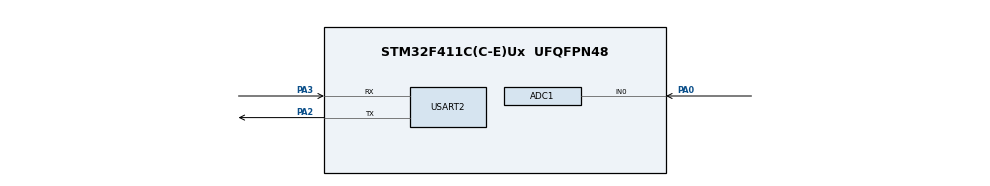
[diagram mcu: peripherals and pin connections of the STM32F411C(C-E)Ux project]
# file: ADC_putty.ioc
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ADC1.Channel-0\#ChannelRegularConversion=ADC_CHANNEL_0
ADC1.DMAContinuousRequests=ENABLE
ADC1.NbrOfConversionFlag=1
ADC1.Rank-0\#ChannelRegularConversion=1
ADC1.SamplingTime-0\#ChannelRegularConversion=ADC_SAMPLETIME_3CYCLES
ADC1.master=1
Dma.ADC1.0.Direction=DMA_PERIPH_TO_MEMORY
Dma.ADC1.0.FIFOMode=DMA_FIFOMODE_DISABLE
Dma.ADC1.0.Instance=DMA2_Stream0
Dma.ADC1.0.MemDataAlignment=DMA_MDATAALIGN_HALFWORD
Dma.ADC1.0.MemInc=DMA_MINC_ENABLE
Dma.ADC1.0.Mode=DMA_NORMAL
Dma.ADC1.0.PeriphDataAlignment=DMA_PDATAALIGN_HALFWORD
Dma.ADC1.0.PeriphInc=DMA_PINC_DISABLE
Dma.ADC1.0.Priority=DMA_PRIORITY_LOW
Dma.Request0=ADC1
Mcu.Family=STM32F4
Mcu.Name=STM32F411C(C-E)Ux
Mcu.Package=UFQFPN48
NVIC.ADC_IRQn=true\:0\:0\:false\:false\:true\:true\:true\:true
NVIC.DMA2_Stream0_IRQn=true\:0\:0\:false\:false\:true\:false\:true\:true
NVIC.PriorityGroup=NVIC_PRIORITYGROUP_4
NVIC.TIM2_IRQn=true\:0\:0\:false\:false\:true\:true\:true\:true
PA0-WKUP.Signal=ADCx_IN0
PA2.Mode=Asynchronous
PA2.Signal=USART2_TX
PA3.Mode=Asynchronous
PA3.Signal=USART2_RX
ProjectManager.HeapSize=0x200
ProjectManager.StackSize=0x400
ProjectManager.TargetToolchain=STM32CubeIDE
RCC.48MHZClocksFreq_Value=168000000
RCC.AHBFreq_Value=16000000
RCC.APB1CLKDivider=RCC_HCLK_DIV2
RCC.APB1Freq_Value=8000000
RCC.APB1TimFreq_Value=16000000
RCC.APB2Freq_Value=16000000
RCC.APB2TimFreq_Value=16000000
RCC.CortexFreq_Value=16000000
RCC.HCLKFreq_Value=16000000
RCC.HSE_VALUE=25000000
RCC.HSI_VALUE=16000000
RCC.LSE_VALUE=32768
RCC.PLLM=8
RCC.PLLN=336
RCC.PLLP=RCC_PLLP_DIV4
RCC.SYSCLKFreq_VALUE=16000000
RCC.VCOOutputFreq_Value=672000000
SH.ADCx_IN0.0=ADC1_IN0,IN0
TIM2.Prescaler=8399
TIM2.TIM_MasterOutputTrigger=TIM_TRGO_UPDATE
USART2.VirtualMode=VM_ASYNC
VP_TIM2_VS_ClockSourceINT.Mode=Internal
board=custom

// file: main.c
/* USER CODE BEGIN Header */
/**
  ******************************************************************************
  * @file           : main.c
  * @brief          : Main program body
  ******************************************************************************
  * @attention
  *
  * Copyright (c) 2026 STMicroelectronics.
  * All rights reserved.
  *
  * This software is licensed under terms that can be found in the LICENSE file
  * in the root directory of this software component.
  * If no LICENSE file comes with this software, it is provided AS-IS.
  *
  ******************************************************************************
  */
/* USER CODE END Header */
#include "main.h"
#include <stdio.h>
#include <string.h>

ADC_HandleTypeDef hadc1;
DMA_HandleTypeDef hdma_adc1;

TIM_HandleTypeDef htim2;

UART_HandleTypeDef huart2;

/* USER CODE BEGIN PV */
uint16_t adc_buffer[1];
/* USER CODE END PV */

void SystemClock_Config(void);
static void MX_GPIO_Init(void);
static void MX_DMA_Init(void);
static void MX_ADC1_Init(void);
static void MX_TIM2_Init(void);
static void MX_USART2_UART_Init(void);

/* USER CODE BEGIN 0 */
uint16_t adc_buffer[1];
/* USER CODE END 0 */

int main(void)
{

  /* MCU Configuration--------------------------------------------------------*/

  /* Reset of all peripherals, Initializes the Flash interface and the Systick. */
  HAL_Init();

  /* Configure the system clock */
  SystemClock_Config();

  /* USER CODE BEGIN SysInit */
  MX_GPIO_Init();
  MX_DMA_Init();
  MX_ADC1_Init();
  MX_TIM2_Init();
  MX_USART2_UART_Init();
  /* USER CODE END SysInit */

  /* Initialize all configured peripherals */
  MX_GPIO_Init();
  MX_DMA_Init();
  MX_ADC1_Init();
  MX_TIM2_Init();
  MX_USART2_UART_Init();
  /* USER CODE BEGIN 2 */
  HAL_TIM_Base_Start_IT(&htim2);   // Start Timer
  /* USER CODE END 2 */

  /* Infinite loop */
  while (1)
  {
	  uint16_t adc_value = 2048;
	  uint16_t voltage_mv = (adc_value * 3300) / 4095; // in mV

	//  char msg[50];
	 // int len = sprintf(msg, "ADC=%d Voltage=%dmV\r\n", adc_value, voltage_mv);
	//  HAL_UART_Transmit(&huart2, (uint8_t*)msg, len, HAL_MAX_DELAY);
	  printf("ADC=%d Voltage=%dmV\n", adc_buffer[0], voltage_mv);
	  HAL_Delay(1000);
  }
}

void SystemClock_Config(void)
{
  RCC_OscInitTypeDef RCC_OscInitStruct = {0};
  RCC_ClkInitTypeDef RCC_ClkInitStruct = {0};

  /** Configure the main internal regulator output voltage
  */
  __HAL_RCC_PWR_CLK_ENABLE();
  __HAL_PWR_VOLTAGESCALING_CONFIG(PWR_REGULATOR_VOLTAGE_SCALE1);

  /** Initializes the RCC Oscillators according to the specified parameters
  * in the RCC_OscInitTypeDef structure.
  */
  RCC_OscInitStruct.OscillatorType = RCC_OSCILLATORTYPE_HSI;
  RCC_OscInitStruct.HSIState = RCC_HSI_ON;
  RCC_OscInitStruct.HSICalibrationValue = RCC_HSICALIBRATION_DEFAULT;
  RCC_OscInitStruct.PLL.PLLState = RCC_PLL_NONE;
  if (HAL_RCC_OscConfig(&RCC_OscInitStruct) != HAL_OK)
  {
    Error_Handler();
  }

  /** Initializes the CPU, AHB and APB buses clocks
  */
  RCC_ClkInitStruct.ClockType = RCC_CLOCKTYPE_HCLK|RCC_CLOCKTYPE_SYSCLK
                              |RCC_CLOCKTYPE_PCLK1|RCC_CLOCKTYPE_PCLK2;
  RCC_ClkInitStruct.SYSCLKSource = RCC_SYSCLKSOURCE_HSI;
  RCC_ClkInitStruct.AHBCLKDivider = RCC_SYSCLK_DIV1;
  RCC_ClkInitStruct.APB1CLKDivider = RCC_HCLK_DIV1;
  RCC_ClkInitStruct.APB2CLKDivider = RCC_HCLK_DIV1;

  if (HAL_RCC_ClockConfig(&RCC_ClkInitStruct, FLASH_LATENCY_0) != HAL_OK)
  {
    Error_Handler();
  }
}

static void MX_ADC1_Init(void)
{

  ADC_ChannelConfTypeDef sConfig = {0};

  /** Configure the global features of the ADC (Clock, Resolution, Data Alignment and number of conversion)
  */
  hadc1.Instance = ADC1;
  hadc1.Init.ClockPrescaler = ADC_CLOCK_SYNC_PCLK_DIV2;
  hadc1.Init.Resolution = ADC_RESOLUTION_12B;
  hadc1.Init.ScanConvMode = DISABLE;
  hadc1.Init.ContinuousConvMode = DISABLE;
  hadc1.Init.DiscontinuousConvMode = DISABLE;
  hadc1.Init.ExternalTrigConvEdge = ADC_EXTERNALTRIGCONVEDGE_NONE;
  hadc1.Init.ExternalTrigConv = ADC_SOFTWARE_START;
  hadc1.Init.DataAlign = ADC_DATAALIGN_RIGHT;
  hadc1.Init.NbrOfConversion = 1;
  hadc1.Init.DMAContinuousRequests = ENABLE;
  hadc1.Init.EOCSelection = ADC_EOC_SINGLE_CONV;
  if (HAL_ADC_Init(&hadc1) != HAL_OK)
  {
    Error_Handler();
  }

  /** Configure for the selected ADC regular channel its corresponding rank in the sequencer and its sample time.
  */
  sConfig.Channel = ADC_CHANNEL_0;
  sConfig.Rank = 1;
  sConfig.SamplingTime = ADC_SAMPLETIME_3CYCLES;
  if (HAL_ADC_ConfigChannel(&hadc1, &sConfig) != HAL_OK)
  {
    Error_Handler();
  }

}

static void MX_TIM2_Init(void)
{

  TIM_ClockConfigTypeDef sClockSourceConfig = {0};
  TIM_MasterConfigTypeDef sMasterConfig = {0};

  htim2.Instance = TIM2;
  htim2.Init.Prescaler = 8399;
  htim2.Init.CounterMode = TIM_COUNTERMODE_UP;
  htim2.Init.Period = 4294967295;
  htim2.Init.ClockDivision = TIM_CLOCKDIVISION_DIV1;
  htim2.Init.AutoReloadPreload = TIM_AUTORELOAD_PRELOAD_DISABLE;
  if (HAL_TIM_Base_Init(&htim2) != HAL_OK)
  {
    Error_Handler();
  }
  sClockSourceConfig.ClockSource = TIM_CLOCKSOURCE_INTERNAL;
  if (HAL_TIM_ConfigClockSource(&htim2, &sClockSourceConfig) != HAL_OK)
  {
    Error_Handler();
  }
  sMasterConfig.MasterOutputTrigger = TIM_TRGO_UPDATE;
  sMasterConfig.MasterSlaveMode = TIM_MASTERSLAVEMODE_DISABLE;
  if (HAL_TIMEx_MasterConfigSynchronization(&htim2, &sMasterConfig) != HAL_OK)
  {
    Error_Handler();
  }

}

static void MX_USART2_UART_Init(void)
{

  huart2.Instance = USART2;
  huart2.Init.BaudRate = 115200;
  huart2.Init.WordLength = UART_WORDLENGTH_8B;
  huart2.Init.StopBits = UART_STOPBITS_1;
  huart2.Init.Parity = UART_PARITY_NONE;
  huart2.Init.Mode = UART_MODE_TX_RX;
  huart2.Init.HwFlowCtl = UART_HWCONTROL_NONE;
  huart2.Init.OverSampling = UART_OVERSAMPLING_16;
  if (HAL_UART_Init(&huart2) != HAL_OK)
  {
    Error_Handler();
  }

}

static void MX_DMA_Init(void)
{

  /* DMA controller clock enable */
  __HAL_RCC_DMA2_CLK_ENABLE();

  /* DMA interrupt init */
  /* DMA2_Stream0_IRQn interrupt configuration */
  HAL_NVIC_SetPriority(DMA2_Stream0_IRQn, 0, 0);
  HAL_NVIC_EnableIRQ(DMA2_Stream0_IRQn);

}

static void MX_GPIO_Init(void)
{

  /* GPIO Ports Clock Enable */
  __HAL_RCC_GPIOA_CLK_ENABLE();

}

/* USER CODE BEGIN 4 */
void HAL_TIM_PeriodElapsedCallback(TIM_HandleTypeDef *htim)
{
  if (htim->Instance == TIM2)
  {
    HAL_ADC_Start_DMA(&hadc1, (uint32_t*)adc_buffer, 1);
  }
}
uint16_t adc_buffer[1];

void HAL_ADC_ConvCpltCallback(ADC_HandleTypeDef* hadc)
{
  char msg[50];

  if (hadc->Instance == ADC1)
  {
    sprintf(msg, "ADC Value: %d\r\n", adc_buffer[0]);
    HAL_UART_Transmit(&huart2, (uint8_t*)msg, strlen(msg), HAL_MAX_DELAY);
  }
}
/* USER CODE END 4 */

void Error_Handler(void)
{
  __disable_irq();
  while (1)
  {
  }
}
